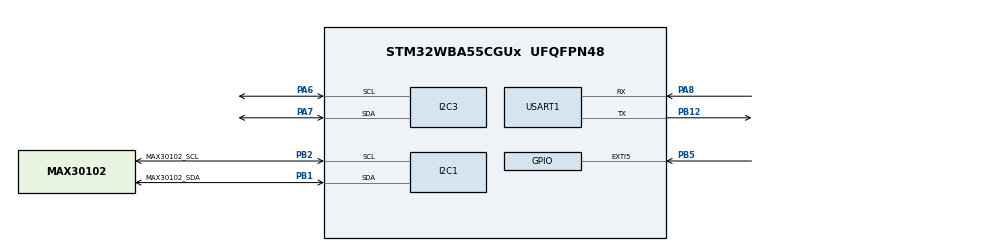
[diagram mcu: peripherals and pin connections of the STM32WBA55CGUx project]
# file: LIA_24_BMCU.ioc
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CORTEX_M33_NS.userName=CORTEX_M33
I2C1.Timing=0x10C0ECFF
I2C3.Timing=0x10C0ECFF
Mcu.Family=STM32WBA
Mcu.Name=STM32WBA55CGUx
Mcu.Package=UFQFPN48
NUCLEO-WBA55CG.BUTTON=0
NUCLEO-WBA55CG.BUTTON2=0
NUCLEO-WBA55CG.BUTTON3=0
NUCLEO-WBA55CG.LD1=false
NUCLEO-WBA55CG.LD2=false
NUCLEO-WBA55CG.LD3=false
NUCLEO-WBA55CG.VCP=false
NVIC.EXTI5_IRQn=true\:0\:0\:false\:false\:true\:true\:true\:true
NVIC.PriorityGroup=NVIC_PRIORITYGROUP_4
OSC_IN.GPIO_Label=RCC_OSC_IN
OSC_IN.Mode=HSE-External-Oscillator
OSC_IN.Signal=RCC_OSC_IN
OSC_OUT.GPIO_Label=RCC_OSC_OUT
OSC_OUT.Mode=HSE-External-Oscillator
OSC_OUT.Signal=RCC_OSC_OUT
PA13\ (JTMS/SWDIO).GPIO_Label=DEBUG_JTMS-SWDIO
PA13\ (JTMS/SWDIO).Signal=DEBUG_JTMS-SWDIO
PA14\ (JTCK/SWCLK).GPIO_Label=DEBUG_JTCK-SWCLK
PA14\ (JTCK/SWCLK).Signal=DEBUG_JTCK-SWCLK
PA6.Mode=I2C
PA6.Signal=I2C3_SCL
PA7.Mode=I2C
PA7.Signal=I2C3_SDA
PA8.Mode=Asynchronous
PA8.Signal=USART1_RX
PB1.GPIO_Label=MAX30102_SDA
PB1.GPIO_Pu=GPIO_NOPULL
PB1.GPIO_Speed=GPIO_SPEED_FREQ_HIGH
PB1.Mode=I2C
PB1.Signal=I2C1_SDA
PB12.Mode=Asynchronous
PB12.Signal=USART1_TX
PB2.GPIO_Label=MAX30102_SCL
PB2.GPIO_Speed=GPIO_SPEED_FREQ_HIGH
PB2.Mode=I2C
PB2.Signal=I2C1_SCL
PB5.GPIO_ModeDefaultEXTI=GPIO_MODE_IT_FALLING
PB5.GPIO_PuPd=GPIO_PULLUP
PB5.Signal=GPXTI5
PC14-OSC32_IN.GPIO_Label=RCC_OSC32_IN
PC14-OSC32_IN.Mode=LSE-External-Oscillator
PC14-OSC32_IN.Signal=RCC_OSC32_IN
PC15-OSC32_OUT.Mode=LSE-External-Oscillator
PC15-OSC32_OUT.Signal=RCC_OSC32_OUT
ProjectManager.HeapSize=0x200
ProjectManager.StackSize=0x400
ProjectManager.TargetToolchain=Makefile
RCC.ADCFreq_Value=100000000
RCC.AHB5CLKDivider=DIV4
RCC.AHBFreq_Value=100000000
RCC.APB1Freq_Value=100000000
RCC.APB1TimFreq_Value=100000000
RCC.APB2Freq_Value=100000000
RCC.APB2TimFreq_Value=100000000
RCC.CortexFreq_Value=12500000
RCC.HCLKFreq_Value=100000000
RCC.HSE_VALUE=32000000
RCC.HSI_VALUE=16000000
RCC.LSI1_VALUE=32000
RCC.LSI2_VALUE=32000
RCC.PLLFRACN=4096
RCC.PLLN=12
RCC.PWR_Regulator_Voltage_Scale=PWR_REGULATOR_VOLTAGE_SCALE1
RCC.RTCClockSelection=RCC_RTCCLKSOURCE_LSE
RCC.SYSCLKFreq_VALUE=100000000
RCC.SYSCLKSourceVirtual=RCC_SYSCLKSOURCE_PLLCLK
RCC.VCOOutputFreq_Value=200000000
USART1.VirtualMode-Asynchronous=VM_ASYNC
VP_CORTEX_M33_NS_VS_Hclk.Mode=Hclk_Mode
VP_ICACHE_VS_ICACHE.Mode=DirectMappedCache
VP_MEMORYMAP_VS_MEMORYMAP.Mode=CurAppReg
VP_NUCLEO-WBA55CG_VS_BSP_COMMON.Mode=COMMON
VP_PWR_VS_SECSignals.Mode=Security/Privilege
board=NUCLEO-WBA55CG

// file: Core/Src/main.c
/* USER CODE BEGIN Header */
/**
  ******************************************************************************
  * @file           : main.c
  * @brief          : Main program body
  ******************************************************************************
  * @attention
  *
  * Copyright (c) 2025 STMicroelectronics.
  * All rights reserved.
  *
  * This software is licensed under terms that can be found in the LICENSE file
  * in the root directory of this software component.
  * If no LICENSE file comes with this software, it is provided AS-IS.
  *
  ******************************************************************************
  */
/* USER CODE END Header */
#include "main.h"

/* USER CODE BEGIN Includes */
#include <stdio.h>
#include "max_sensor.h"
#include "string.h"
#include "stm32wbaxx_hal.h"
#include "uart.h"
#include <stdint.h>
#include "lis2dw12_reg.h"
#include <stm32wbaxx_hal_rcc.h>
#include <stm32wba55xx.h>
/* USER CODE END Includes */

/* USER CODE BEGIN PD */
#define ROLL_MIN_THRESHOLD -80
#define ROLL_MAX_THRESHOLD -35

/* USER CODE END PD */

I2C_HandleTypeDef hi2c1;
I2C_HandleTypeDef hi2c3;

UART_HandleTypeDef huart1;

/* USER CODE BEGIN PV */
volatile uint8_t MAX30102_Flag = 0;
extern float current_roll;
extern float current_pitch;

/* USER CODE END PV */

void SystemClock_Config(void);
static void MX_GPIO_Init(void);
static void MX_I2C1_Init(void);
static void MX_ICACHE_Init(void);
static void MX_USART1_UART_Init(void);
static void MX_I2C3_Init(void);

int main(void)
{

  /* MCU Configuration--------------------------------------------------------*/

  /* Reset of all peripherals, Initializes the Flash interface and the Systick. */
  HAL_Init();

  /* Configure the system clock */
  SystemClock_Config();

  /* Initialize all configured peripherals */
  MX_GPIO_Init();
  MX_I2C1_Init();
  MX_ICACHE_Init();
  MX_USART1_UART_Init();
  MX_I2C3_Init();
  /* USER CODE BEGIN 2 */
  uart_Init();
  FIFO_LED_DATA fifoledData;
  MAX30102_resetRegister();
  MAX30102_initFIFO();
  uint8_t test_buffer[] = "Hello does this work";
  //Sampling & pulse width
  MAX30102_setSampleRate(_100SPS);
  MAX30102_setPulseWidth(_411_US);

  // LED current (mA)
  MAX30102_setLedCurrent(RED_LED, 5); // Saturates pretty easily depending on surrounding lights
  MAX30102_setLedCurrent(IR_LED, 1); // Shouldn't be needed

  MAX30102_resetFIFO();

  //Mode
  MAX30102_setMeasMode(HEART_RATE);
  /* USER CODE END 2 */

  /* Infinite loop */
  /* USER CODE BEGIN WHILE */
  while (1)
  {
    //lis2dw12_activity();
    //lis2dw12_single_tap();
    lis2dw12_orientation();
    if (current_roll < 80 && current_roll > 35)
    {
      fifoledData = MAX30102_read_FIFO();

      max_Sensor = MAX30102_update(fifoledData);
      MAX30102_resetFIFO();

      if (INTERRUPT == 1)
      {
        if (MAX30102_Flag)
        {
          MAX30102_Flag = 0;
          fifoledData = MAX30102_read_FIFO();

          max_Sensor = MAX30102_update(fifoledData);

          MAX30102_clearInterrupt();

        }
      }
      else
      {
        // fifoledData = MAX30102_read_FIFO();

        // max_Sensor = MAX30102_update(fifoledData);

        // MAX30102_resetFIFO();

        //HAL_Delay(10);
      }
    }
    else
    {
      //out of range
    }

    MAX30102_displayData();
    //   MAX30102_registerData();
    // }
    /* USER CODE END WHILE */

  }
}

void SystemClock_Config(void)
{
  RCC_OscInitTypeDef RCC_OscInitStruct = {0};
  RCC_ClkInitTypeDef RCC_ClkInitStruct = {0};

  /** Supply configuration update enable
  */
  HAL_PWREx_ConfigSupply(PWR_LDO_SUPPLY);

  /** Configure the main internal regulator output voltage
  */
  if (HAL_PWREx_ControlVoltageScaling(PWR_REGULATOR_VOLTAGE_SCALE1) != HAL_OK)
  {
    Error_Handler();
  }

  /** Initializes the CPU, AHB and APB busses clocks
  */
  RCC_OscInitStruct.OscillatorType = RCC_OSCILLATORTYPE_HSI;
  RCC_OscInitStruct.HSIState = RCC_HSI_ON;
  RCC_OscInitStruct.HSICalibrationValue = RCC_HSICALIBRATION_DEFAULT;
  RCC_OscInitStruct.PLL1.PLLState = RCC_PLL_ON;
  RCC_OscInitStruct.PLL1.PLLSource = RCC_PLLSOURCE_HSI;
  RCC_OscInitStruct.PLL1.PLLM = 1;
  RCC_OscInitStruct.PLL1.PLLN = 12;
  RCC_OscInitStruct.PLL1.PLLP = 2;
  RCC_OscInitStruct.PLL1.PLLQ = 2;
  RCC_OscInitStruct.PLL1.PLLR = 2;
  RCC_OscInitStruct.PLL1.PLLFractional = 4096;
  if (HAL_RCC_OscConfig(&RCC_OscInitStruct) != HAL_OK)
  {
    Error_Handler();
  }

  /** Initializes the CPU, AHB and APB busses clocks
  */
  RCC_ClkInitStruct.ClockType = RCC_CLOCKTYPE_HCLK|RCC_CLOCKTYPE_SYSCLK
                              |RCC_CLOCKTYPE_PCLK1|RCC_CLOCKTYPE_PCLK2
                              |RCC_CLOCKTYPE_PCLK7|RCC_CLOCKTYPE_HCLK5;
  RCC_ClkInitStruct.SYSCLKSource = RCC_SYSCLKSOURCE_PLLCLK;
  RCC_ClkInitStruct.AHBCLKDivider = RCC_SYSCLK_DIV1;
  RCC_ClkInitStruct.APB1CLKDivider = RCC_HCLK_DIV1;
  RCC_ClkInitStruct.APB2CLKDivider = RCC_HCLK_DIV1;
  RCC_ClkInitStruct.APB7CLKDivider = RCC_HCLK_DIV1;
  RCC_ClkInitStruct.AHB5_PLL1_CLKDivider = RCC_SYSCLK_PLL1_DIV4;
  RCC_ClkInitStruct.AHB5_HSEHSI_CLKDivider = RCC_SYSCLK_HSEHSI_DIV1;

  if (HAL_RCC_ClockConfig(&RCC_ClkInitStruct, FLASH_LATENCY_3) != HAL_OK)
  {
    Error_Handler();
  }
}

static void MX_I2C1_Init(void)
{

  hi2c1.Instance = I2C1;
  hi2c1.Init.Timing = 0x10C0ECFF;
  hi2c1.Init.OwnAddress1 = 0;
  hi2c1.Init.AddressingMode = I2C_ADDRESSINGMODE_7BIT;
  hi2c1.Init.DualAddressMode = I2C_DUALADDRESS_DISABLE;
  hi2c1.Init.OwnAddress2 = 0;
  hi2c1.Init.OwnAddress2Masks = I2C_OA2_NOMASK;
  hi2c1.Init.GeneralCallMode = I2C_GENERALCALL_DISABLE;
  hi2c1.Init.NoStretchMode = I2C_NOSTRETCH_DISABLE;
  if (HAL_I2C_Init(&hi2c1) != HAL_OK)
  {
    Error_Handler();
  }

  /** Configure Analogue filter
  */
  if (HAL_I2CEx_ConfigAnalogFilter(&hi2c1, I2C_ANALOGFILTER_ENABLE) != HAL_OK)
  {
    Error_Handler();
  }

  /** Configure Digital filter
  */
  if (HAL_I2CEx_ConfigDigitalFilter(&hi2c1, 0) != HAL_OK)
  {
    Error_Handler();
  }

}

static void MX_I2C3_Init(void)
{

  hi2c3.Instance = I2C3;
  hi2c3.Init.Timing = 0x10C0ECFF;
  hi2c3.Init.OwnAddress1 = 0;
  hi2c3.Init.AddressingMode = I2C_ADDRESSINGMODE_7BIT;
  hi2c3.Init.DualAddressMode = I2C_DUALADDRESS_DISABLE;
  hi2c3.Init.OwnAddress2 = 0;
  hi2c3.Init.OwnAddress2Masks = I2C_OA2_NOMASK;
  hi2c3.Init.GeneralCallMode = I2C_GENERALCALL_DISABLE;
  hi2c3.Init.NoStretchMode = I2C_NOSTRETCH_DISABLE;
  if (HAL_I2C_Init(&hi2c3) != HAL_OK)
  {
    Error_Handler();
  }

  /** Configure Analogue filter
  */
  if (HAL_I2CEx_ConfigAnalogFilter(&hi2c3, I2C_ANALOGFILTER_ENABLE) != HAL_OK)
  {
    Error_Handler();
  }

  /** Configure Digital filter
  */
  if (HAL_I2CEx_ConfigDigitalFilter(&hi2c3, 0) != HAL_OK)
  {
    Error_Handler();
  }

}

static void MX_ICACHE_Init(void)
{

  /** Enable instruction cache in 1-way (direct mapped cache)
  */
  if (HAL_ICACHE_ConfigAssociativityMode(ICACHE_1WAY) != HAL_OK)
  {
    Error_Handler();
  }
  if (HAL_ICACHE_Enable() != HAL_OK)
  {
    Error_Handler();
  }

}

static void MX_USART1_UART_Init(void)
{

  huart1.Instance = USART1;
  huart1.Init.BaudRate = 115200;
  huart1.Init.WordLength = UART_WORDLENGTH_8B;
  huart1.Init.StopBits = UART_STOPBITS_1;
  huart1.Init.Parity = UART_PARITY_NONE;
  huart1.Init.Mode = UART_MODE_TX_RX;
  huart1.Init.HwFlowCtl = UART_HWCONTROL_NONE;
  huart1.Init.OverSampling = UART_OVERSAMPLING_16;
  huart1.Init.OneBitSampling = UART_ONE_BIT_SAMPLE_DISABLE;
  huart1.Init.ClockPrescaler = UART_PRESCALER_DIV1;
  huart1.AdvancedInit.AdvFeatureInit = UART_ADVFEATURE_NO_INIT;
  if (HAL_UART_Init(&huart1) != HAL_OK)
  {
    Error_Handler();
  }
  if (HAL_UARTEx_SetTxFifoThreshold(&huart1, UART_TXFIFO_THRESHOLD_1_8) != HAL_OK)
  {
    Error_Handler();
  }
  if (HAL_UARTEx_SetRxFifoThreshold(&huart1, UART_RXFIFO_THRESHOLD_1_8) != HAL_OK)
  {
    Error_Handler();
  }
  if (HAL_UARTEx_DisableFifoMode(&huart1) != HAL_OK)
  {
    Error_Handler();
  }

}

static void MX_GPIO_Init(void)
{
  GPIO_InitTypeDef GPIO_InitStruct = {0};

  /* GPIO Ports Clock Enable */
  __HAL_RCC_GPIOB_CLK_ENABLE();
  __HAL_RCC_GPIOA_CLK_ENABLE();
  __HAL_RCC_GPIOC_CLK_ENABLE();

  /*Configure GPIO pin : PB5 */
  GPIO_InitStruct.Pin = GPIO_PIN_5;
  GPIO_InitStruct.Mode = GPIO_MODE_IT_FALLING;
  GPIO_InitStruct.Pull = GPIO_PULLUP;
  HAL_GPIO_Init(GPIOB, &GPIO_InitStruct);

  /* EXTI interrupt init*/
  HAL_NVIC_SetPriority(EXTI5_IRQn, 0, 0);
  HAL_NVIC_EnableIRQ(EXTI5_IRQn);

  /* USER CODE BEGIN MX_GPIO_Init_2 */

  /* Configure PA11 (USART2 TX) and PA12 (USART2 RX) */
  GPIO_InitStruct.Pin = GPIO_PIN_11 | GPIO_PIN_12;
  GPIO_InitStruct.Mode = GPIO_MODE_AF_PP;  // Alternate function, push-pull
  GPIO_InitStruct.Pull = GPIO_NOPULL;      // No pull-up, no pull-down
  GPIO_InitStruct.Speed = GPIO_SPEED_FREQ_HIGH;
  GPIO_InitStruct.Alternate = GPIO_AF3_USART2;  // AF3 for USART2

  HAL_GPIO_Init(GPIOA, &GPIO_InitStruct);

  /* USER CODE END MX_GPIO_Init_2 */
}

void Error_Handler(void)
{
  __disable_irq();
  while (1)
  {
  }
}
